VERSION 5.7 ;
  NOWIREEXTENSIONATPIN ON ;
  DIVIDERCHAR "/" ;
  BUSBITCHARS "[]" ;
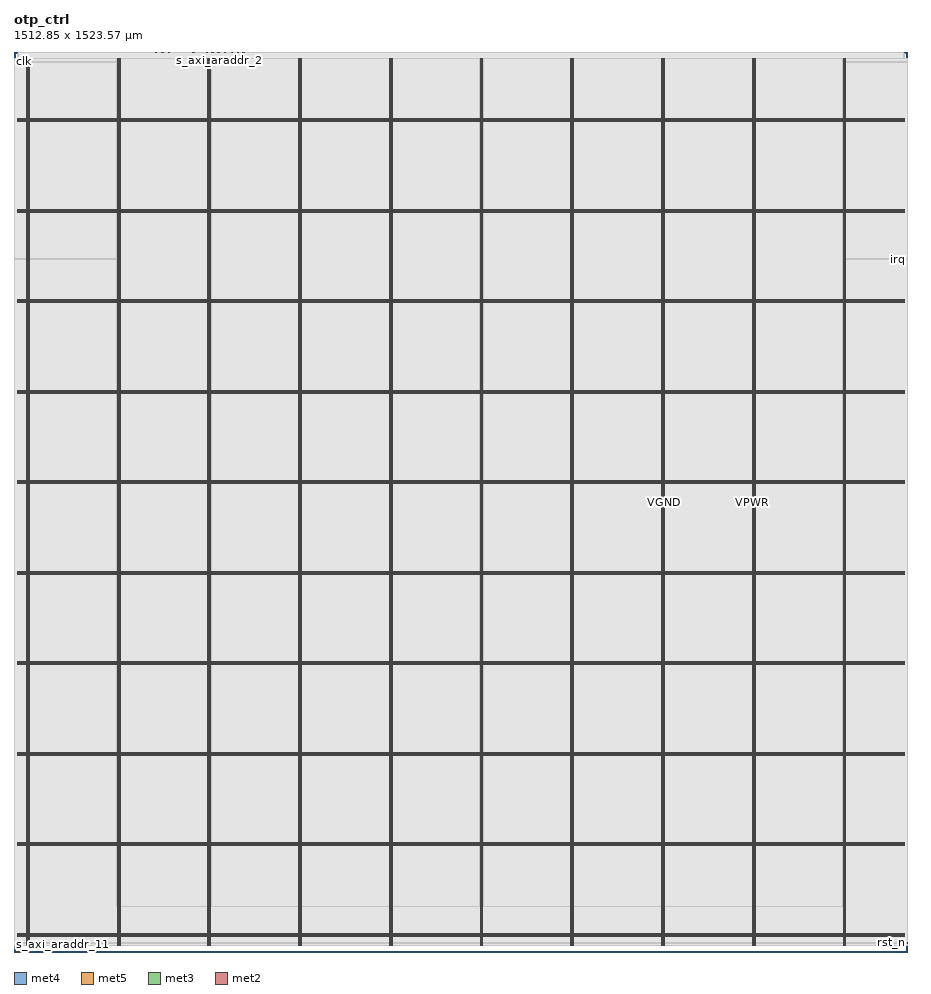
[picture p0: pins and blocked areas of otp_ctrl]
MACRO otp_ctrl
  CLASS BLOCK ;
  FOREIGN otp_ctrl ;
  ORIGIN 0.000 0.000 ;
  SIZE 1512.850 BY 1523.570 ;
  PIN VGND
    DIRECTION INOUT ;
    USE GROUND ;
    PORT
      LAYER met4 ;
        RECT 24.340 10.640 25.940 1512.560 ;
    END
    PORT
      LAYER met4 ;
        RECT 177.940 10.640 179.540 1512.560 ;
    END
    PORT
      LAYER met4 ;
        RECT 331.540 10.640 333.140 1512.560 ;
    END
    PORT
      LAYER met4 ;
        RECT 485.140 10.640 486.740 1512.560 ;
    END
    PORT
      LAYER met4 ;
        RECT 638.740 10.640 640.340 1512.560 ;
    END
    PORT
      LAYER met4 ;
        RECT 792.340 10.640 793.940 1512.560 ;
    END
    PORT
      LAYER met4 ;
        RECT 945.940 10.640 947.540 1512.560 ;
    END
    PORT
      LAYER met4 ;
        RECT 1099.540 10.640 1101.140 1512.560 ;
    END
    PORT
      LAYER met4 ;
        RECT 1253.140 10.640 1254.740 1512.560 ;
    END
    PORT
      LAYER met4 ;
        RECT 1406.740 10.640 1408.340 1512.560 ;
    END
    PORT
      LAYER met5 ;
        RECT 5.520 30.030 1506.960 31.630 ;
    END
    PORT
      LAYER met5 ;
        RECT 5.520 183.210 1506.960 184.810 ;
    END
    PORT
      LAYER met5 ;
        RECT 5.520 336.390 1506.960 337.990 ;
    END
    PORT
      LAYER met5 ;
        RECT 5.520 489.570 1506.960 491.170 ;
    END
    PORT
      LAYER met5 ;
        RECT 5.520 642.750 1506.960 644.350 ;
    END
    PORT
      LAYER met5 ;
        RECT 5.520 795.930 1506.960 797.530 ;
    END
    PORT
      LAYER met5 ;
        RECT 5.520 949.110 1506.960 950.710 ;
    END
    PORT
      LAYER met5 ;
        RECT 5.520 1102.290 1506.960 1103.890 ;
    END
    PORT
      LAYER met5 ;
        RECT 5.520 1255.470 1506.960 1257.070 ;
    END
    PORT
      LAYER met5 ;
        RECT 5.520 1408.650 1506.960 1410.250 ;
    END
  END VGND
  PIN VPWR
    DIRECTION INOUT ;
    USE POWER ;
    PORT
      LAYER met4 ;
        RECT 21.040 10.640 22.640 1512.560 ;
    END
    PORT
      LAYER met4 ;
        RECT 174.640 10.640 176.240 1512.560 ;
    END
    PORT
      LAYER met4 ;
        RECT 328.240 10.640 329.840 1512.560 ;
    END
    PORT
      LAYER met4 ;
        RECT 481.840 10.640 483.440 1512.560 ;
    END
    PORT
      LAYER met4 ;
        RECT 635.440 10.640 637.040 1512.560 ;
    END
    PORT
      LAYER met4 ;
        RECT 789.040 10.640 790.640 1512.560 ;
    END
    PORT
      LAYER met4 ;
        RECT 942.640 10.640 944.240 1512.560 ;
    END
    PORT
      LAYER met4 ;
        RECT 1096.240 10.640 1097.840 1512.560 ;
    END
    PORT
      LAYER met4 ;
        RECT 1249.840 10.640 1251.440 1512.560 ;
    END
    PORT
      LAYER met4 ;
        RECT 1403.440 10.640 1405.040 1512.560 ;
    END
    PORT
      LAYER met5 ;
        RECT 5.520 26.730 1506.960 28.330 ;
    END
    PORT
      LAYER met5 ;
        RECT 5.520 179.910 1506.960 181.510 ;
    END
    PORT
      LAYER met5 ;
        RECT 5.520 333.090 1506.960 334.690 ;
    END
    PORT
      LAYER met5 ;
        RECT 5.520 486.270 1506.960 487.870 ;
    END
    PORT
      LAYER met5 ;
        RECT 5.520 639.450 1506.960 641.050 ;
    END
    PORT
      LAYER met5 ;
        RECT 5.520 792.630 1506.960 794.230 ;
    END
    PORT
      LAYER met5 ;
        RECT 5.520 945.810 1506.960 947.410 ;
    END
    PORT
      LAYER met5 ;
        RECT 5.520 1098.990 1506.960 1100.590 ;
    END
    PORT
      LAYER met5 ;
        RECT 5.520 1252.170 1506.960 1253.770 ;
    END
    PORT
      LAYER met5 ;
        RECT 5.520 1405.350 1506.960 1406.950 ;
    END
  END VPWR
  PIN clk
    DIRECTION INPUT ;
    USE SIGNAL ;
    ANTENNAGATEAREA 1.286700 ;
    ANTENNADIFFAREA 0.434700 ;
    PORT
      LAYER met3 ;
        RECT 0.000 1506.920 0.600 1507.520 ;
    END
  END clk
  PIN irq
    DIRECTION OUTPUT ;
    USE SIGNAL ;
    ANTENNAGATEAREA 0.434700 ;
    ANTENNADIFFAREA 1.137600 ;
    PORT
      LAYER met3 ;
        RECT 1512.250 1172.360 1512.850 1172.960 ;
    END
  END irq
  PIN rst_n
    DIRECTION INPUT ;
    USE SIGNAL ;
    ANTENNAGATEAREA 0.647700 ;
    ANTENNADIFFAREA 0.434700 ;
    PORT
      LAYER met3 ;
        RECT 1512.250 15.000 1512.850 15.600 ;
    END
  END rst_n
  PIN s_axi_araddr_0
    DIRECTION INPUT ;
    USE SIGNAL ;
    PORT
      LAYER met2 ;
        RECT 1.930 0.000 2.210 0.280 ;
    END
  END s_axi_araddr_0
  PIN s_axi_araddr_1
    DIRECTION INPUT ;
    USE SIGNAL ;
    PORT
      LAYER met2 ;
        RECT 2.850 0.000 3.130 0.280 ;
    END
  END s_axi_araddr_1
  PIN s_axi_araddr_10
    DIRECTION INPUT ;
    USE SIGNAL ;
    PORT
      LAYER met2 ;
        RECT 3.770 0.000 4.050 0.280 ;
    END
  END s_axi_araddr_10
  PIN s_axi_araddr_11
    DIRECTION INPUT ;
    USE SIGNAL ;
    PORT
      LAYER met2 ;
        RECT 4.690 0.000 4.970 0.280 ;
    END
  END s_axi_araddr_11
  PIN s_axi_araddr_2
    DIRECTION INPUT ;
    USE SIGNAL ;
    ANTENNAGATEAREA 0.647700 ;
    ANTENNADIFFAREA 0.434700 ;
    PORT
      LAYER met2 ;
        RECT 346.930 1523.290 347.210 1523.570 ;
    END
  END s_axi_araddr_2
  PIN s_axi_araddr_3
    DIRECTION INPUT ;
    USE SIGNAL ;
    ANTENNAGATEAREA 0.560700 ;
    ANTENNADIFFAREA 0.434700 ;
    PORT
      LAYER met2 ;
        RECT 346.010 1523.290 346.290 1523.570 ;
    END
  END s_axi_araddr_3
  PIN s_axi_araddr_4
    DIRECTION INPUT ;
    USE SIGNAL ;
    ANTENNAGATEAREA 0.647700 ;
    ANTENNADIFFAREA 0.434700 ;
    PORT
      LAYER met2 ;
        RECT 344.170 1523.290 344.450 1523.570 ;
    END
  END s_axi_araddr_4
  PIN s_axi_araddr_5
    DIRECTION INPUT ;
    USE SIGNAL ;
    PORT
      LAYER met2 ;
        RECT 5.610 0.000 5.890 0.280 ;
    END
  END s_axi_araddr_5
  PIN s_axi_araddr_6
    DIRECTION INPUT ;
    USE SIGNAL ;
    PORT
      LAYER met2 ;
        RECT 6.530 0.000 6.810 0.280 ;
    END
  END s_axi_araddr_6
  PIN s_axi_araddr_7
    DIRECTION INPUT ;
    USE SIGNAL ;
    PORT
      LAYER met2 ;
        RECT 7.450 0.000 7.730 0.280 ;
    END
  END s_axi_araddr_7
  PIN s_axi_araddr_8
    DIRECTION INPUT ;
    USE SIGNAL ;
    PORT
      LAYER met2 ;
        RECT 8.370 0.000 8.650 0.280 ;
    END
  END s_axi_araddr_8
  PIN s_axi_araddr_9
    DIRECTION INPUT ;
    USE SIGNAL ;
    PORT
      LAYER met2 ;
        RECT 9.290 0.000 9.570 0.280 ;
    END
  END s_axi_araddr_9
  PIN s_axi_arready
    DIRECTION OUTPUT ;
    USE SIGNAL ;
    ANTENNAGATEAREA 0.434700 ;
    ANTENNADIFFAREA 1.137600 ;
    PORT
      LAYER met2 ;
        RECT 318.410 1523.290 318.690 1523.570 ;
    END
  END s_axi_arready
  PIN s_axi_arvalid
    DIRECTION INPUT ;
    USE SIGNAL ;
    ANTENNAGATEAREA 0.647700 ;
    ANTENNADIFFAREA 0.434700 ;
    PORT
      LAYER met2 ;
        RECT 325.770 1523.290 326.050 1523.570 ;
    END
  END s_axi_arvalid
  PIN s_axi_awaddr_0
    DIRECTION INPUT ;
    USE SIGNAL ;
    PORT
      LAYER met2 ;
        RECT 10.210 0.000 10.490 0.280 ;
    END
  END s_axi_awaddr_0
  PIN s_axi_awaddr_1
    DIRECTION INPUT ;
    USE SIGNAL ;
    PORT
      LAYER met2 ;
        RECT 11.130 0.000 11.410 0.280 ;
    END
  END s_axi_awaddr_1
  PIN s_axi_awaddr_10
    DIRECTION INPUT ;
    USE SIGNAL ;
    PORT
      LAYER met2 ;
        RECT 12.050 0.000 12.330 0.280 ;
    END
  END s_axi_awaddr_10
  PIN s_axi_awaddr_11
    DIRECTION INPUT ;
    USE SIGNAL ;
    PORT
      LAYER met2 ;
        RECT 12.970 0.000 13.250 0.280 ;
    END
  END s_axi_awaddr_11
  PIN s_axi_awaddr_2
    DIRECTION INPUT ;
    USE SIGNAL ;
    ANTENNAGATEAREA 0.647700 ;
    ANTENNADIFFAREA 0.434700 ;
    PORT
      LAYER met2 ;
        RECT 369.010 1523.290 369.290 1523.570 ;
    END
  END s_axi_awaddr_2
  PIN s_axi_awaddr_3
    DIRECTION INPUT ;
    USE SIGNAL ;
    ANTENNAGATEAREA 0.647700 ;
    ANTENNADIFFAREA 0.434700 ;
    PORT
      LAYER met2 ;
        RECT 368.090 1523.290 368.370 1523.570 ;
    END
  END s_axi_awaddr_3
  PIN s_axi_awaddr_4
    DIRECTION INPUT ;
    USE SIGNAL ;
    ANTENNAGATEAREA 0.647700 ;
    ANTENNADIFFAREA 0.434700 ;
    PORT
      LAYER met2 ;
        RECT 380.050 1523.290 380.330 1523.570 ;
    END
  END s_axi_awaddr_4
  PIN s_axi_awaddr_5
    DIRECTION INPUT ;
    USE SIGNAL ;
    PORT
      LAYER met2 ;
        RECT 13.890 0.000 14.170 0.280 ;
    END
  END s_axi_awaddr_5
  PIN s_axi_awaddr_6
    DIRECTION INPUT ;
    USE SIGNAL ;
    PORT
      LAYER met2 ;
        RECT 14.810 0.000 15.090 0.280 ;
    END
  END s_axi_awaddr_6
  PIN s_axi_awaddr_7
    DIRECTION INPUT ;
    USE SIGNAL ;
    PORT
      LAYER met2 ;
        RECT 15.730 0.000 16.010 0.280 ;
    END
  END s_axi_awaddr_7
  PIN s_axi_awaddr_8
    DIRECTION INPUT ;
    USE SIGNAL ;
    PORT
      LAYER met2 ;
        RECT 16.650 0.000 16.930 0.280 ;
    END
  END s_axi_awaddr_8
  PIN s_axi_awaddr_9
    DIRECTION INPUT ;
    USE SIGNAL ;
    PORT
      LAYER met2 ;
        RECT 17.570 0.000 17.850 0.280 ;
    END
  END s_axi_awaddr_9
  PIN s_axi_awready
    DIRECTION OUTPUT ;
    USE SIGNAL ;
    ANTENNAGATEAREA 0.434700 ;
    ANTENNADIFFAREA 1.137600 ;
    PORT
      LAYER met2 ;
        RECT 395.690 1523.290 395.970 1523.570 ;
    END
  END s_axi_awready
  PIN s_axi_awvalid
    DIRECTION INPUT ;
    USE SIGNAL ;
    ANTENNAGATEAREA 0.560700 ;
    ANTENNADIFFAREA 0.434700 ;
    PORT
      LAYER met2 ;
        RECT 379.130 1523.290 379.410 1523.570 ;
    END
  END s_axi_awvalid
  PIN s_axi_bready
    DIRECTION INPUT ;
    USE SIGNAL ;
    ANTENNAGATEAREA 0.560700 ;
    ANTENNADIFFAREA 0.434700 ;
    PORT
      LAYER met2 ;
        RECT 380.970 1523.290 381.250 1523.570 ;
    END
  END s_axi_bready
  PIN s_axi_bresp_0
    DIRECTION OUTPUT ;
    USE SIGNAL ;
    ANTENNAGATEAREA 0.434700 ;
    ANTENNADIFFAREA 1.137600 ;
    PORT
      LAYER met2 ;
        RECT 381.890 1523.290 382.170 1523.570 ;
    END
  END s_axi_bresp_0
  PIN s_axi_bresp_1
    DIRECTION OUTPUT ;
    USE SIGNAL ;
    ANTENNAGATEAREA 0.434700 ;
    ANTENNADIFFAREA 1.137600 ;
    PORT
      LAYER met2 ;
        RECT 394.770 1523.290 395.050 1523.570 ;
    END
  END s_axi_bresp_1
  PIN s_axi_bvalid
    DIRECTION OUTPUT ;
    USE SIGNAL ;
    ANTENNAGATEAREA 0.434700 ;
    ANTENNADIFFAREA 1.137600 ;
    PORT
      LAYER met2 ;
        RECT 391.090 1523.290 391.370 1523.570 ;
    END
  END s_axi_bvalid
  PIN s_axi_rdata_0
    DIRECTION OUTPUT ;
    USE SIGNAL ;
    ANTENNAGATEAREA 0.434700 ;
    ANTENNADIFFAREA 1.137600 ;
    PORT
      LAYER met2 ;
        RECT 315.650 1523.290 315.930 1523.570 ;
    END
  END s_axi_rdata_0
  PIN s_axi_rdata_1
    DIRECTION OUTPUT ;
    USE SIGNAL ;
    ANTENNAGATEAREA 0.434700 ;
    ANTENNADIFFAREA 1.137600 ;
    PORT
      LAYER met2 ;
        RECT 244.810 1523.290 245.090 1523.570 ;
    END
  END s_axi_rdata_1
  PIN s_axi_rdata_10
    DIRECTION OUTPUT ;
    USE SIGNAL ;
    ANTENNAGATEAREA 0.434700 ;
    ANTENNADIFFAREA 1.137600 ;
    PORT
      LAYER met2 ;
        RECT 250.330 1523.290 250.610 1523.570 ;
    END
  END s_axi_rdata_10
  PIN s_axi_rdata_11
    DIRECTION OUTPUT ;
    USE SIGNAL ;
    ANTENNAGATEAREA 0.434700 ;
    ANTENNADIFFAREA 1.137600 ;
    PORT
      LAYER met2 ;
        RECT 254.010 1523.290 254.290 1523.570 ;
    END
  END s_axi_rdata_11
  PIN s_axi_rdata_12
    DIRECTION OUTPUT ;
    USE SIGNAL ;
    ANTENNAGATEAREA 0.434700 ;
    ANTENNADIFFAREA 1.137600 ;
    PORT
      LAYER met2 ;
        RECT 233.770 1523.290 234.050 1523.570 ;
    END
  END s_axi_rdata_12
  PIN s_axi_rdata_13
    DIRECTION OUTPUT ;
    USE SIGNAL ;
    ANTENNAGATEAREA 0.434700 ;
    ANTENNADIFFAREA 1.137600 ;
    PORT
      LAYER met2 ;
        RECT 262.290 1523.290 262.570 1523.570 ;
    END
  END s_axi_rdata_13
  PIN s_axi_rdata_14
    DIRECTION OUTPUT ;
    USE SIGNAL ;
    ANTENNAGATEAREA 0.434700 ;
    ANTENNADIFFAREA 1.137600 ;
    PORT
      LAYER met2 ;
        RECT 267.810 1523.290 268.090 1523.570 ;
    END
  END s_axi_rdata_14
  PIN s_axi_rdata_15
    DIRECTION OUTPUT ;
    USE SIGNAL ;
    ANTENNAGATEAREA 0.434700 ;
    ANTENNADIFFAREA 1.137600 ;
    PORT
      LAYER met2 ;
        RECT 240.210 1523.290 240.490 1523.570 ;
    END
  END s_axi_rdata_15
  PIN s_axi_rdata_16
    DIRECTION OUTPUT ;
    USE SIGNAL ;
    ANTENNAGATEAREA 0.434700 ;
    ANTENNADIFFAREA 1.137600 ;
    PORT
      LAYER met2 ;
        RECT 253.090 1523.290 253.370 1523.570 ;
    END
  END s_axi_rdata_16
  PIN s_axi_rdata_17
    DIRECTION OUTPUT ;
    USE SIGNAL ;
    ANTENNAGATEAREA 0.434700 ;
    ANTENNADIFFAREA 1.137600 ;
    PORT
      LAYER met2 ;
        RECT 263.210 1523.290 263.490 1523.570 ;
    END
  END s_axi_rdata_17
  PIN s_axi_rdata_18
    DIRECTION OUTPUT ;
    USE SIGNAL ;
    ANTENNAGATEAREA 0.434700 ;
    ANTENNADIFFAREA 1.137600 ;
    PORT
      LAYER met2 ;
        RECT 249.410 1523.290 249.690 1523.570 ;
    END
  END s_axi_rdata_18
  PIN s_axi_rdata_19
    DIRECTION OUTPUT ;
    USE SIGNAL ;
    ANTENNAGATEAREA 0.434700 ;
    ANTENNADIFFAREA 1.137600 ;
    PORT
      LAYER met2 ;
        RECT 252.170 1523.290 252.450 1523.570 ;
    END
  END s_axi_rdata_19
  PIN s_axi_rdata_2
    DIRECTION OUTPUT ;
    USE SIGNAL ;
    ANTENNAGATEAREA 0.434700 ;
    ANTENNADIFFAREA 1.137600 ;
    PORT
      LAYER met2 ;
        RECT 337.730 1523.290 338.010 1523.570 ;
    END
  END s_axi_rdata_2
  PIN s_axi_rdata_20
    DIRECTION OUTPUT ;
    USE SIGNAL ;
    ANTENNAGATEAREA 0.434700 ;
    ANTENNADIFFAREA 1.137600 ;
    PORT
      LAYER met2 ;
        RECT 243.890 1523.290 244.170 1523.570 ;
    END
  END s_axi_rdata_20
  PIN s_axi_rdata_21
    DIRECTION OUTPUT ;
    USE SIGNAL ;
    ANTENNAGATEAREA 0.434700 ;
    ANTENNADIFFAREA 1.137600 ;
    PORT
      LAYER met2 ;
        RECT 235.610 1523.290 235.890 1523.570 ;
    END
  END s_axi_rdata_21
  PIN s_axi_rdata_22
    DIRECTION OUTPUT ;
    USE SIGNAL ;
    ANTENNAGATEAREA 0.434700 ;
    ANTENNADIFFAREA 1.137600 ;
    PORT
      LAYER met2 ;
        RECT 236.530 1523.290 236.810 1523.570 ;
    END
  END s_axi_rdata_22
  PIN s_axi_rdata_23
    DIRECTION OUTPUT ;
    USE SIGNAL ;
    ANTENNAGATEAREA 0.434700 ;
    ANTENNADIFFAREA 1.137600 ;
    PORT
      LAYER met2 ;
        RECT 241.130 1523.290 241.410 1523.570 ;
    END
  END s_axi_rdata_23
  PIN s_axi_rdata_24
    DIRECTION OUTPUT ;
    USE SIGNAL ;
    ANTENNAGATEAREA 0.434700 ;
    ANTENNADIFFAREA 1.137600 ;
    PORT
      LAYER met2 ;
        RECT 304.610 1523.290 304.890 1523.570 ;
    END
  END s_axi_rdata_24
  PIN s_axi_rdata_25
    DIRECTION OUTPUT ;
    USE SIGNAL ;
    ANTENNAGATEAREA 0.434700 ;
    ANTENNADIFFAREA 1.137600 ;
    PORT
      LAYER met2 ;
        RECT 234.690 1523.290 234.970 1523.570 ;
    END
  END s_axi_rdata_25
  PIN s_axi_rdata_26
    DIRECTION OUTPUT ;
    USE SIGNAL ;
    ANTENNAGATEAREA 0.434700 ;
    ANTENNADIFFAREA 1.137600 ;
    PORT
      LAYER met2 ;
        RECT 251.250 1523.290 251.530 1523.570 ;
    END
  END s_axi_rdata_26
  PIN s_axi_rdata_27
    DIRECTION OUTPUT ;
    USE SIGNAL ;
    ANTENNAGATEAREA 0.434700 ;
    ANTENNADIFFAREA 1.137600 ;
    PORT
      LAYER met2 ;
        RECT 229.170 1523.290 229.450 1523.570 ;
    END
  END s_axi_rdata_27
  PIN s_axi_rdata_28
    DIRECTION OUTPUT ;
    USE SIGNAL ;
    ANTENNAGATEAREA 0.434700 ;
    ANTENNADIFFAREA 1.137600 ;
    PORT
      LAYER met2 ;
        RECT 242.970 1523.290 243.250 1523.570 ;
    END
  END s_axi_rdata_28
  PIN s_axi_rdata_29
    DIRECTION OUTPUT ;
    USE SIGNAL ;
    ANTENNAGATEAREA 0.434700 ;
    ANTENNADIFFAREA 1.137600 ;
    PORT
      LAYER met2 ;
        RECT 261.370 1523.290 261.650 1523.570 ;
    END
  END s_axi_rdata_29
  PIN s_axi_rdata_3
    DIRECTION OUTPUT ;
    USE SIGNAL ;
    ANTENNAGATEAREA 0.434700 ;
    ANTENNADIFFAREA 1.137600 ;
    PORT
      LAYER met2 ;
        RECT 352.450 1523.290 352.730 1523.570 ;
    END
  END s_axi_rdata_3
  PIN s_axi_rdata_30
    DIRECTION OUTPUT ;
    USE SIGNAL ;
    ANTENNAGATEAREA 0.434700 ;
    ANTENNADIFFAREA 1.137600 ;
    PORT
      LAYER met2 ;
        RECT 302.770 1523.290 303.050 1523.570 ;
    END
  END s_axi_rdata_30
  PIN s_axi_rdata_31
    DIRECTION OUTPUT ;
    USE SIGNAL ;
    ANTENNAGATEAREA 0.434700 ;
    ANTENNADIFFAREA 1.137600 ;
    PORT
      LAYER met2 ;
        RECT 239.290 1523.290 239.570 1523.570 ;
    END
  END s_axi_rdata_31
  PIN s_axi_rdata_4
    DIRECTION OUTPUT ;
    USE SIGNAL ;
    ANTENNAGATEAREA 0.434700 ;
    ANTENNADIFFAREA 1.137600 ;
    PORT
      LAYER met2 ;
        RECT 341.410 1523.290 341.690 1523.570 ;
    END
  END s_axi_rdata_4
  PIN s_axi_rdata_5
    DIRECTION OUTPUT ;
    USE SIGNAL ;
    ANTENNAGATEAREA 0.434700 ;
    ANTENNADIFFAREA 1.137600 ;
    PORT
      LAYER met2 ;
        RECT 348.770 1523.290 349.050 1523.570 ;
    END
  END s_axi_rdata_5
  PIN s_axi_rdata_6
    DIRECTION OUTPUT ;
    USE SIGNAL ;
    ANTENNAGATEAREA 0.434700 ;
    ANTENNADIFFAREA 1.137600 ;
    PORT
      LAYER met2 ;
        RECT 289.890 1523.290 290.170 1523.570 ;
    END
  END s_axi_rdata_6
  PIN s_axi_rdata_7
    DIRECTION OUTPUT ;
    USE SIGNAL ;
    ANTENNAGATEAREA 0.434700 ;
    ANTENNADIFFAREA 1.137600 ;
    PORT
      LAYER met2 ;
        RECT 256.770 1523.290 257.050 1523.570 ;
    END
  END s_axi_rdata_7
  PIN s_axi_rdata_8
    DIRECTION OUTPUT ;
    USE SIGNAL ;
    ANTENNAGATEAREA 0.434700 ;
    ANTENNADIFFAREA 1.137600 ;
    PORT
      LAYER met2 ;
        RECT 232.850 1523.290 233.130 1523.570 ;
    END
  END s_axi_rdata_8
  PIN s_axi_rdata_9
    DIRECTION OUTPUT ;
    USE SIGNAL ;
    ANTENNAGATEAREA 0.434700 ;
    ANTENNADIFFAREA 1.137600 ;
    PORT
      LAYER met2 ;
        RECT 245.730 1523.290 246.010 1523.570 ;
    END
  END s_axi_rdata_9
  PIN s_axi_rready
    DIRECTION INPUT ;
    USE SIGNAL ;
    ANTENNAGATEAREA 0.560700 ;
    ANTENNADIFFAREA 0.434700 ;
    PORT
      LAYER met2 ;
        RECT 329.450 1523.290 329.730 1523.570 ;
    END
  END s_axi_rready
  PIN s_axi_rresp_0
    DIRECTION OUTPUT ;
    USE SIGNAL ;
    ANTENNAGATEAREA 0.434700 ;
    ANTENNADIFFAREA 1.137600 ;
    PORT
      LAYER met2 ;
        RECT 278.850 1523.290 279.130 1523.570 ;
    END
  END s_axi_rresp_0
  PIN s_axi_rresp_1
    DIRECTION OUTPUT ;
    USE SIGNAL ;
    ANTENNAGATEAREA 0.434700 ;
    ANTENNADIFFAREA 1.137600 ;
    PORT
      LAYER met2 ;
        RECT 231.930 1523.290 232.210 1523.570 ;
    END
  END s_axi_rresp_1
  PIN s_axi_rvalid
    DIRECTION OUTPUT ;
    USE SIGNAL ;
    ANTENNAGATEAREA 0.434700 ;
    ANTENNADIFFAREA 1.137600 ;
    PORT
      LAYER met2 ;
        RECT 326.690 1523.290 326.970 1523.570 ;
    END
  END s_axi_rvalid
  PIN s_axi_wdata_0
    DIRECTION INPUT ;
    USE SIGNAL ;
    ANTENNAGATEAREA 0.647700 ;
    ANTENNADIFFAREA 0.434700 ;
    PORT
      LAYER met2 ;
        RECT 354.290 1523.290 354.570 1523.570 ;
    END
  END s_axi_wdata_0
  PIN s_axi_wdata_1
    DIRECTION INPUT ;
    USE SIGNAL ;
    ANTENNAGATEAREA 0.647700 ;
    ANTENNADIFFAREA 0.434700 ;
    PORT
      LAYER met2 ;
        RECT 340.490 1523.290 340.770 1523.570 ;
    END
  END s_axi_wdata_1
  PIN s_axi_wdata_10
    DIRECTION INPUT ;
    USE SIGNAL ;
    ANTENNAGATEAREA 0.647700 ;
    ANTENNADIFFAREA 0.434700 ;
    PORT
      LAYER met2 ;
        RECT 310.130 1523.290 310.410 1523.570 ;
    END
  END s_axi_wdata_10
  PIN s_axi_wdata_11
    DIRECTION INPUT ;
    USE SIGNAL ;
    ANTENNAGATEAREA 0.647700 ;
    ANTENNADIFFAREA 0.434700 ;
    PORT
      LAYER met2 ;
        RECT 305.530 1523.290 305.810 1523.570 ;
    END
  END s_axi_wdata_11
  PIN s_axi_wdata_12
    DIRECTION INPUT ;
    USE SIGNAL ;
    ANTENNAGATEAREA 0.647700 ;
    ANTENNADIFFAREA 0.434700 ;
    PORT
      LAYER met2 ;
        RECT 309.210 1523.290 309.490 1523.570 ;
    END
  END s_axi_wdata_12
  PIN s_axi_wdata_13
    DIRECTION INPUT ;
    USE SIGNAL ;
    ANTENNAGATEAREA 0.647700 ;
    ANTENNADIFFAREA 0.434700 ;
    PORT
      LAYER met2 ;
        RECT 317.490 1523.290 317.770 1523.570 ;
    END
  END s_axi_wdata_13
  PIN s_axi_wdata_14
    DIRECTION INPUT ;
    USE SIGNAL ;
    ANTENNAGATEAREA 0.647700 ;
    ANTENNADIFFAREA 0.434700 ;
    PORT
      LAYER met2 ;
        RECT 338.650 1523.290 338.930 1523.570 ;
    END
  END s_axi_wdata_14
  PIN s_axi_wdata_15
    DIRECTION INPUT ;
    USE SIGNAL ;
    ANTENNAGATEAREA 0.647700 ;
    ANTENNADIFFAREA 0.434700 ;
    PORT
      LAYER met2 ;
        RECT 313.810 1523.290 314.090 1523.570 ;
    END
  END s_axi_wdata_15
  PIN s_axi_wdata_16
    DIRECTION INPUT ;
    USE SIGNAL ;
    ANTENNAGATEAREA 0.647700 ;
    ANTENNADIFFAREA 0.434700 ;
    PORT
      LAYER met2 ;
        RECT 333.130 1523.290 333.410 1523.570 ;
    END
  END s_axi_wdata_16
  PIN s_axi_wdata_17
    DIRECTION INPUT ;
    USE SIGNAL ;
    ANTENNAGATEAREA 0.647700 ;
    ANTENNADIFFAREA 0.434700 ;
    PORT
      LAYER met2 ;
        RECT 343.250 1523.290 343.530 1523.570 ;
    END
  END s_axi_wdata_17
  PIN s_axi_wdata_18
    DIRECTION INPUT ;
    USE SIGNAL ;
    ANTENNAGATEAREA 0.647700 ;
    ANTENNADIFFAREA 0.434700 ;
    PORT
      LAYER met2 ;
        RECT 336.810 1523.290 337.090 1523.570 ;
    END
  END s_axi_wdata_18
  PIN s_axi_wdata_19
    DIRECTION INPUT ;
    USE SIGNAL ;
    ANTENNAGATEAREA 0.647700 ;
    ANTENNADIFFAREA 0.434700 ;
    PORT
      LAYER met2 ;
        RECT 356.130 1523.290 356.410 1523.570 ;
    END
  END s_axi_wdata_19
  PIN s_axi_wdata_2
    DIRECTION INPUT ;
    USE SIGNAL ;
    ANTENNAGATEAREA 0.647700 ;
    ANTENNADIFFAREA 0.434700 ;
    PORT
      LAYER met2 ;
        RECT 321.170 1523.290 321.450 1523.570 ;
    END
  END s_axi_wdata_2
  PIN s_axi_wdata_20
    DIRECTION INPUT ;
    USE SIGNAL ;
    ANTENNAGATEAREA 0.647700 ;
    ANTENNADIFFAREA 0.434700 ;
    PORT
      LAYER met2 ;
        RECT 357.050 1523.290 357.330 1523.570 ;
    END
  END s_axi_wdata_20
  PIN s_axi_wdata_21
    DIRECTION INPUT ;
    USE SIGNAL ;
    ANTENNAGATEAREA 0.647700 ;
    ANTENNADIFFAREA 0.434700 ;
    PORT
      LAYER met2 ;
        RECT 361.650 1523.290 361.930 1523.570 ;
    END
  END s_axi_wdata_21
  PIN s_axi_wdata_22
    DIRECTION INPUT ;
    USE SIGNAL ;
    ANTENNAGATEAREA 0.647700 ;
    ANTENNADIFFAREA 0.434700 ;
    PORT
      LAYER met2 ;
        RECT 355.210 1523.290 355.490 1523.570 ;
    END
  END s_axi_wdata_22
  PIN s_axi_wdata_23
    DIRECTION INPUT ;
    USE SIGNAL ;
    ANTENNAGATEAREA 0.647700 ;
    ANTENNADIFFAREA 0.434700 ;
    PORT
      LAYER met2 ;
        RECT 370.850 1523.290 371.130 1523.570 ;
    END
  END s_axi_wdata_23
  PIN s_axi_wdata_24
    DIRECTION INPUT ;
    USE SIGNAL ;
    ANTENNAGATEAREA 0.647700 ;
    ANTENNADIFFAREA 0.434700 ;
    PORT
      LAYER met2 ;
        RECT 360.730 1523.290 361.010 1523.570 ;
    END
  END s_axi_wdata_24
  PIN s_axi_wdata_25
    DIRECTION INPUT ;
    USE SIGNAL ;
    ANTENNAGATEAREA 0.647700 ;
    ANTENNADIFFAREA 0.434700 ;
    PORT
      LAYER met2 ;
        RECT 374.530 1523.290 374.810 1523.570 ;
    END
  END s_axi_wdata_25
  PIN s_axi_wdata_26
    DIRECTION INPUT ;
    USE SIGNAL ;
    ANTENNAGATEAREA 0.647700 ;
    ANTENNADIFFAREA 0.434700 ;
    PORT
      LAYER met2 ;
        RECT 383.730 1523.290 384.010 1523.570 ;
    END
  END s_axi_wdata_26
  PIN s_axi_wdata_27
    DIRECTION INPUT ;
    USE SIGNAL ;
    ANTENNAGATEAREA 0.647700 ;
    ANTENNADIFFAREA 0.434700 ;
    PORT
      LAYER met2 ;
        RECT 382.810 1523.290 383.090 1523.570 ;
    END
  END s_axi_wdata_27
  PIN s_axi_wdata_28
    DIRECTION INPUT ;
    USE SIGNAL ;
    ANTENNAGATEAREA 0.647700 ;
    ANTENNADIFFAREA 0.434700 ;
    PORT
      LAYER met2 ;
        RECT 359.810 1523.290 360.090 1523.570 ;
    END
  END s_axi_wdata_28
  PIN s_axi_wdata_29
    DIRECTION INPUT ;
    USE SIGNAL ;
    ANTENNAGATEAREA 0.647700 ;
    ANTENNADIFFAREA 0.434700 ;
    PORT
      LAYER met2 ;
        RECT 384.650 1523.290 384.930 1523.570 ;
    END
  END s_axi_wdata_29
  PIN s_axi_wdata_3
    DIRECTION INPUT ;
    USE SIGNAL ;
    ANTENNAGATEAREA 0.647700 ;
    ANTENNADIFFAREA 0.434700 ;
    PORT
      LAYER met2 ;
        RECT 345.090 1523.290 345.370 1523.570 ;
    END
  END s_axi_wdata_3
  PIN s_axi_wdata_30
    DIRECTION INPUT ;
    USE SIGNAL ;
    ANTENNAGATEAREA 0.647700 ;
    ANTENNADIFFAREA 0.434700 ;
    PORT
      LAYER met2 ;
        RECT 387.410 1523.290 387.690 1523.570 ;
    END
  END s_axi_wdata_30
  PIN s_axi_wdata_31
    DIRECTION INPUT ;
    USE SIGNAL ;
    ANTENNAGATEAREA 0.647700 ;
    ANTENNADIFFAREA 0.434700 ;
    PORT
      LAYER met2 ;
        RECT 357.970 1523.290 358.250 1523.570 ;
    END
  END s_axi_wdata_31
  PIN s_axi_wdata_4
    DIRECTION INPUT ;
    USE SIGNAL ;
    ANTENNAGATEAREA 0.647700 ;
    ANTENNADIFFAREA 0.434700 ;
    PORT
      LAYER met2 ;
        RECT 307.370 1523.290 307.650 1523.570 ;
    END
  END s_axi_wdata_4
  PIN s_axi_wdata_5
    DIRECTION INPUT ;
    USE SIGNAL ;
    ANTENNAGATEAREA 0.647700 ;
    ANTENNADIFFAREA 0.434700 ;
    PORT
      LAYER met2 ;
        RECT 328.530 1523.290 328.810 1523.570 ;
    END
  END s_axi_wdata_5
  PIN s_axi_wdata_6
    DIRECTION INPUT ;
    USE SIGNAL ;
    ANTENNAGATEAREA 0.647700 ;
    ANTENNADIFFAREA 0.434700 ;
    PORT
      LAYER met2 ;
        RECT 322.090 1523.290 322.370 1523.570 ;
    END
  END s_axi_wdata_6
  PIN s_axi_wdata_7
    DIRECTION INPUT ;
    USE SIGNAL ;
    ANTENNAGATEAREA 0.647700 ;
    ANTENNADIFFAREA 0.434700 ;
    PORT
      LAYER met2 ;
        RECT 311.050 1523.290 311.330 1523.570 ;
    END
  END s_axi_wdata_7
  PIN s_axi_wdata_8
    DIRECTION INPUT ;
    USE SIGNAL ;
    ANTENNAGATEAREA 0.647700 ;
    ANTENNADIFFAREA 0.434700 ;
    PORT
      LAYER met2 ;
        RECT 308.290 1523.290 308.570 1523.570 ;
    END
  END s_axi_wdata_8
  PIN s_axi_wdata_9
    DIRECTION INPUT ;
    USE SIGNAL ;
    ANTENNAGATEAREA 0.647700 ;
    ANTENNADIFFAREA 0.434700 ;
    PORT
      LAYER met2 ;
        RECT 332.210 1523.290 332.490 1523.570 ;
    END
  END s_axi_wdata_9
  PIN s_axi_wready
    DIRECTION OUTPUT ;
    USE SIGNAL ;
    ANTENNAGATEAREA 0.434700 ;
    ANTENNADIFFAREA 1.137600 ;
    PORT
      LAYER met2 ;
        RECT 353.370 1523.290 353.650 1523.570 ;
    END
  END s_axi_wready
  PIN s_axi_wstrb_0
    DIRECTION INPUT ;
    USE SIGNAL ;
    ANTENNAGATEAREA 0.647700 ;
    ANTENNADIFFAREA 0.434700 ;
    PORT
      LAYER met2 ;
        RECT 334.970 1523.290 335.250 1523.570 ;
    END
  END s_axi_wstrb_0
  PIN s_axi_wstrb_1
    DIRECTION INPUT ;
    USE SIGNAL ;
    ANTENNAGATEAREA 0.647700 ;
    ANTENNADIFFAREA 0.434700 ;
    PORT
      LAYER met2 ;
        RECT 306.450 1523.290 306.730 1523.570 ;
    END
  END s_axi_wstrb_1
  PIN s_axi_wstrb_2
    DIRECTION INPUT ;
    USE SIGNAL ;
    ANTENNAGATEAREA 0.647700 ;
    ANTENNADIFFAREA 0.434700 ;
    PORT
      LAYER met2 ;
        RECT 349.690 1523.290 349.970 1523.570 ;
    END
  END s_axi_wstrb_2
  PIN s_axi_wstrb_3
    DIRECTION INPUT ;
    USE SIGNAL ;
    ANTENNAGATEAREA 0.647700 ;
    ANTENNADIFFAREA 0.434700 ;
    PORT
      LAYER met2 ;
        RECT 385.570 1523.290 385.850 1523.570 ;
    END
  END s_axi_wstrb_3
  PIN s_axi_wvalid
    DIRECTION INPUT ;
    USE SIGNAL ;
    ANTENNAGATEAREA 0.647700 ;
    ANTENNADIFFAREA 0.434700 ;
    PORT
      LAYER met2 ;
        RECT 389.250 1523.290 389.530 1523.570 ;
    END
  END s_axi_wvalid
  OBS
      LAYER nwell ;
        RECT 5.330 10.795 1507.150 1512.405 ;
      LAYER li1 ;
        RECT 5.520 10.795 1506.960 1512.405 ;
      LAYER met1 ;
        RECT 5.520 10.640 1506.960 1521.800 ;
      LAYER met2 ;
        RECT 7.000 1523.010 228.890 1523.290 ;
        RECT 229.730 1523.010 231.650 1523.290 ;
        RECT 232.490 1523.010 232.570 1523.290 ;
        RECT 233.410 1523.010 233.490 1523.290 ;
        RECT 234.330 1523.010 234.410 1523.290 ;
        RECT 235.250 1523.010 235.330 1523.290 ;
        RECT 236.170 1523.010 236.250 1523.290 ;
        RECT 237.090 1523.010 239.010 1523.290 ;
        RECT 239.850 1523.010 239.930 1523.290 ;
        RECT 240.770 1523.010 240.850 1523.290 ;
        RECT 241.690 1523.010 242.690 1523.290 ;
        RECT 243.530 1523.010 243.610 1523.290 ;
        RECT 244.450 1523.010 244.530 1523.290 ;
        RECT 245.370 1523.010 245.450 1523.290 ;
        RECT 246.290 1523.010 249.130 1523.290 ;
        RECT 249.970 1523.010 250.050 1523.290 ;
        RECT 250.890 1523.010 250.970 1523.290 ;
        RECT 251.810 1523.010 251.890 1523.290 ;
        RECT 252.730 1523.010 252.810 1523.290 ;
        RECT 253.650 1523.010 253.730 1523.290 ;
        RECT 254.570 1523.010 256.490 1523.290 ;
        RECT 257.330 1523.010 261.090 1523.290 ;
        RECT 261.930 1523.010 262.010 1523.290 ;
        RECT 262.850 1523.010 262.930 1523.290 ;
        RECT 263.770 1523.010 267.530 1523.290 ;
        RECT 268.370 1523.010 278.570 1523.290 ;
        RECT 279.410 1523.010 289.610 1523.290 ;
        RECT 290.450 1523.010 302.490 1523.290 ;
        RECT 303.330 1523.010 304.330 1523.290 ;
        RECT 305.170 1523.010 305.250 1523.290 ;
        RECT 306.090 1523.010 306.170 1523.290 ;
        RECT 307.010 1523.010 307.090 1523.290 ;
        RECT 307.930 1523.010 308.010 1523.290 ;
        RECT 308.850 1523.010 308.930 1523.290 ;
        RECT 309.770 1523.010 309.850 1523.290 ;
        RECT 310.690 1523.010 310.770 1523.290 ;
        RECT 311.610 1523.010 313.530 1523.290 ;
        RECT 314.370 1523.010 315.370 1523.290 ;
        RECT 316.210 1523.010 317.210 1523.290 ;
        RECT 318.050 1523.010 318.130 1523.290 ;
        RECT 318.970 1523.010 320.890 1523.290 ;
        RECT 321.730 1523.010 321.810 1523.290 ;
        RECT 322.650 1523.010 325.490 1523.290 ;
        RECT 326.330 1523.010 326.410 1523.290 ;
        RECT 327.250 1523.010 328.250 1523.290 ;
        RECT 329.090 1523.010 329.170 1523.290 ;
        RECT 330.010 1523.010 331.930 1523.290 ;
        RECT 332.770 1523.010 332.850 1523.290 ;
        RECT 333.690 1523.010 334.690 1523.290 ;
        RECT 335.530 1523.010 336.530 1523.290 ;
        RECT 337.370 1523.010 337.450 1523.290 ;
        RECT 338.290 1523.010 338.370 1523.290 ;
        RECT 339.210 1523.010 340.210 1523.290 ;
        RECT 341.050 1523.010 341.130 1523.290 ;
        RECT 341.970 1523.010 342.970 1523.290 ;
        RECT 343.810 1523.010 343.890 1523.290 ;
        RECT 344.730 1523.010 344.810 1523.290 ;
        RECT 345.650 1523.010 345.730 1523.290 ;
        RECT 346.570 1523.010 346.650 1523.290 ;
        RECT 347.490 1523.010 348.490 1523.290 ;
        RECT 349.330 1523.010 349.410 1523.290 ;
        RECT 350.250 1523.010 352.170 1523.290 ;
        RECT 353.010 1523.010 353.090 1523.290 ;
        RECT 353.930 1523.010 354.010 1523.290 ;
        RECT 354.850 1523.010 354.930 1523.290 ;
        RECT 355.770 1523.010 355.850 1523.290 ;
        RECT 356.690 1523.010 356.770 1523.290 ;
        RECT 357.610 1523.010 357.690 1523.290 ;
        RECT 358.530 1523.010 359.530 1523.290 ;
        RECT 360.370 1523.010 360.450 1523.290 ;
        RECT 361.290 1523.010 361.370 1523.290 ;
        RECT 362.210 1523.010 367.810 1523.290 ;
        RECT 368.650 1523.010 368.730 1523.290 ;
        RECT 369.570 1523.010 370.570 1523.290 ;
        RECT 371.410 1523.010 374.250 1523.290 ;
        RECT 375.090 1523.010 378.850 1523.290 ;
        RECT 379.690 1523.010 379.770 1523.290 ;
        RECT 380.610 1523.010 380.690 1523.290 ;
        RECT 381.530 1523.010 381.610 1523.290 ;
        RECT 382.450 1523.010 382.530 1523.290 ;
        RECT 383.370 1523.010 383.450 1523.290 ;
        RECT 384.290 1523.010 384.370 1523.290 ;
        RECT 385.210 1523.010 385.290 1523.290 ;
        RECT 386.130 1523.010 387.130 1523.290 ;
        RECT 387.970 1523.010 388.970 1523.290 ;
        RECT 389.810 1523.010 390.810 1523.290 ;
        RECT 391.650 1523.010 394.490 1523.290 ;
        RECT 395.330 1523.010 395.410 1523.290 ;
        RECT 396.250 1523.010 1505.950 1523.290 ;
        RECT 7.000 10.695 1505.950 1523.010 ;
      LAYER met3 ;
        RECT 0.600 1507.920 1512.250 1512.485 ;
        RECT 1.000 1506.520 1512.250 1507.920 ;
        RECT 0.600 1173.360 1512.250 1506.520 ;
        RECT 0.600 1171.960 1511.850 1173.360 ;
        RECT 0.600 16.000 1512.250 1171.960 ;
        RECT 0.600 14.600 1511.850 16.000 ;
        RECT 0.600 10.715 1512.250 14.600 ;
      LAYER met4 ;
        RECT 173.255 77.695 174.240 1512.145 ;
        RECT 176.640 77.695 177.540 1512.145 ;
        RECT 179.940 77.695 327.840 1512.145 ;
        RECT 330.240 77.695 331.140 1512.145 ;
        RECT 333.540 77.695 481.440 1512.145 ;
        RECT 483.840 77.695 484.740 1512.145 ;
        RECT 487.140 77.695 635.040 1512.145 ;
        RECT 637.440 77.695 638.340 1512.145 ;
        RECT 640.740 77.695 788.640 1512.145 ;
        RECT 791.040 77.695 791.940 1512.145 ;
        RECT 794.340 77.695 942.240 1512.145 ;
        RECT 944.640 77.695 945.540 1512.145 ;
        RECT 947.940 77.695 1095.840 1512.145 ;
        RECT 1098.240 77.695 1099.140 1512.145 ;
        RECT 1101.540 77.695 1249.440 1512.145 ;
        RECT 1251.840 77.695 1252.740 1512.145 ;
        RECT 1255.140 77.695 1403.040 1512.145 ;
        RECT 1405.440 77.695 1406.340 1512.145 ;
  END
END otp_ctrl
END LIBRARY

